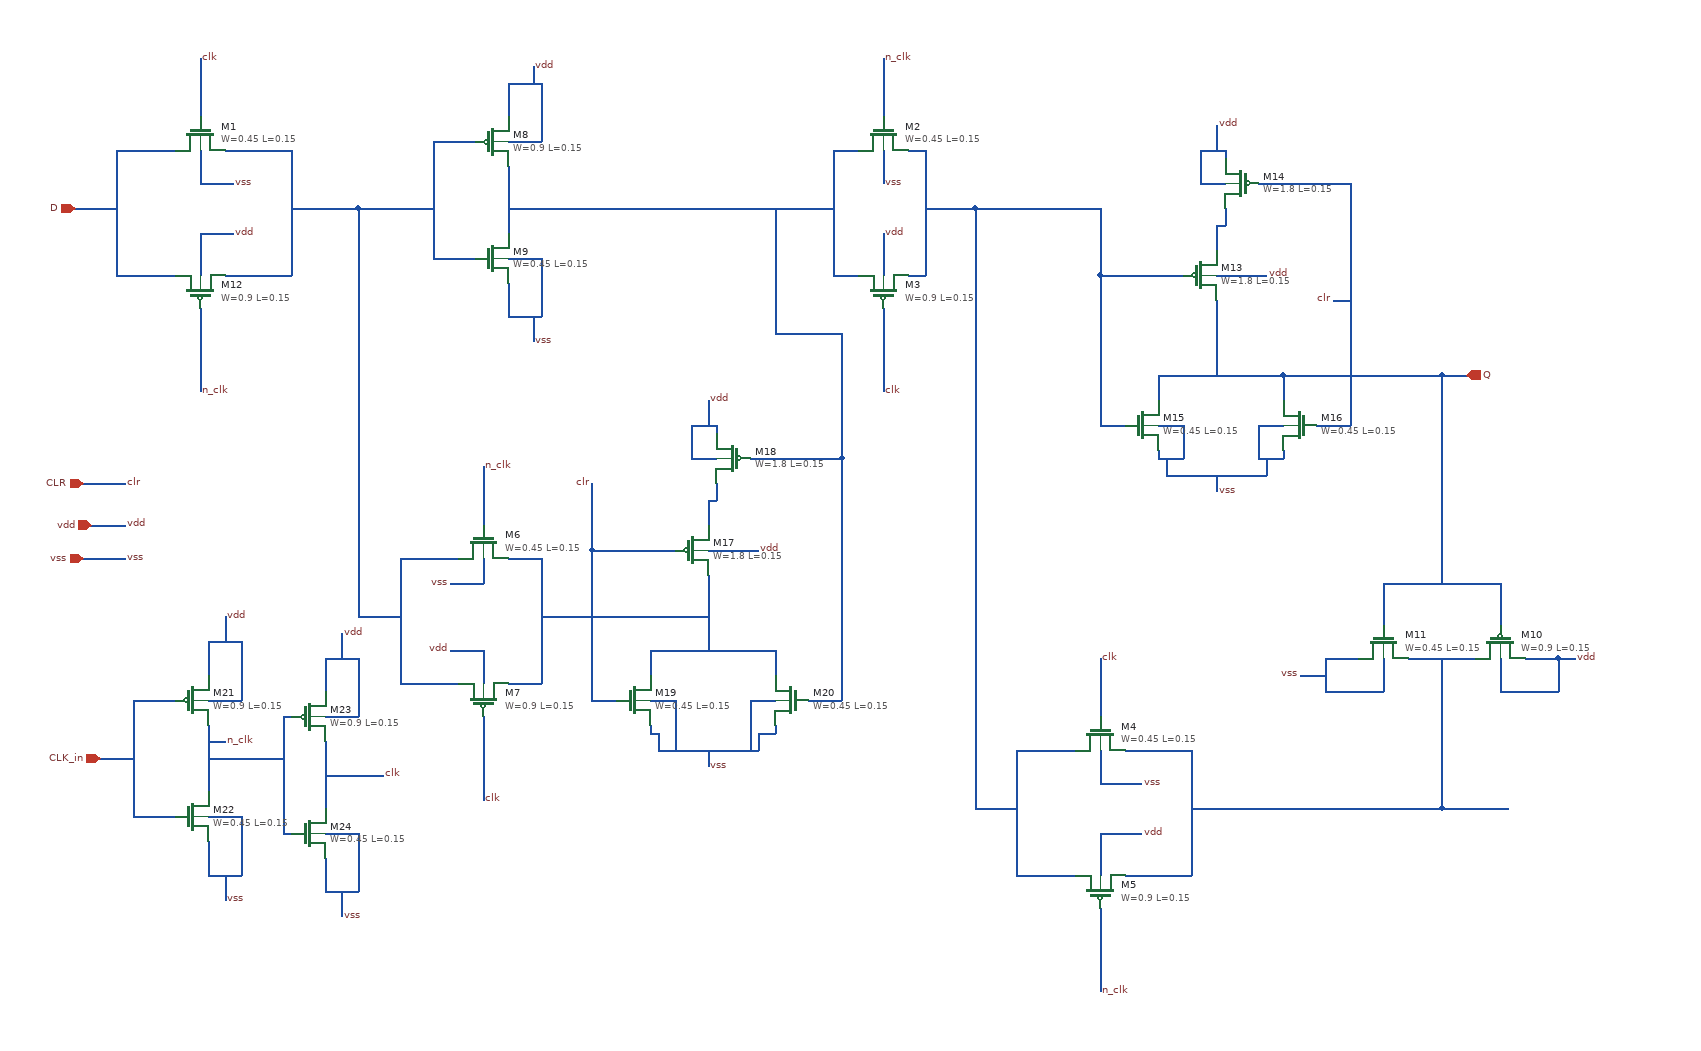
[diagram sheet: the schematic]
v {xschem version=2.9.9 file_version=1.2 }
G {}
K {}
V {}
S {}
E {}
N -920 -130 -910 -130 { lab=D}
N -920 -280 -910 -280 { lab=D}
N -850 -130 -770 -130 { lab=#net1}
N -770 -280 -770 -130 { lab=#net1}
N -850 -280 -770 -280 { lab=#net1}
N -770 -210 -690 -210 { lab=#net1}
N -880 -90 -880 10 { lab=n_clk}
N -880 -390 -880 -320 { lab=clk}
N -980 -280 -920 -280 { lab=D}
N -980 -280 -980 -130 { lab=D}
N -980 -130 -920 -130 { lab=D}
N -1030 -210 -980 -210 { lab=D}
N -60 -170 -60 -130 { lab=vdd}
N -100 -130 -90 -130 { lab=#net2}
N -60 -280 -60 -250 { lab=vss}
N -100 -280 -90 -280 { lab=#net2}
N -10 -280 -10 -130 { lab=#net3}
N -60 -90 -60 10 { lab=clk}
N -60 -390 -60 -320 { lab=n_clk}
N -270 -210 -220 -210 { lab=#net2}
N 200 550 200 590 { lab=vdd}
N 160 590 170 590 { lab=#net3}
N 200 440 200 470 { lab=vss}
N 160 440 170 440 { lab=#net3}
N 230 590 310 590 { lab=#net4}
N 310 440 310 590 { lab=#net4}
N 230 440 310 440 { lab=#net4}
N 310 510 390 510 { lab=#net4}
N 200 630 200 730 { lab=n_clk}
N 200 330 200 400 { lab=clk}
N 100 440 160 440 { lab=#net3}
N 100 440 100 590 { lab=#net3}
N 100 590 160 590 { lab=#net3}
N 50 510 100 510 { lab=#net3}
N -540 320 -540 360 { lab=vdd}
N -580 320 -540 320 { lab=vdd}
N -580 360 -570 360 { lab=#net1}
N -540 210 -540 240 { lab=vss}
N -580 240 -540 240 { lab=vss}
N -580 210 -570 210 { lab=#net1}
N -540 400 -540 500 { lab=clk}
N -540 100 -540 170 { lab=n_clk}
N -640 210 -580 210 { lab=#net1}
N -640 210 -640 360 { lab=#net1}
N -640 360 -580 360 { lab=#net1}
N -690 280 -640 280 { lab=#net1}
N -690 -210 -690 280 { lab=#net1}
N -600 -150 -550 -150 { lab=#net1}
N -600 -290 -600 -150 { lab=#net1}
N -600 -290 -550 -290 { lab=#net1}
N -510 -260 -510 -180 { lab=#net2}
N -510 -150 -470 -150 { lab=vss}
N -470 -150 -470 -80 { lab=vss}
N -510 -80 -470 -80 { lab=vss}
N -510 -120 -510 -80 { lab=vss}
N -510 -290 -470 -290 { lab=vdd}
N -470 -360 -470 -290 { lab=vdd}
N -510 -360 -470 -360 { lab=vdd}
N -510 -360 -510 -320 { lab=vdd}
N -690 -210 -600 -210 { lab=#net1}
N -510 -210 -270 -210 { lab=#net2}
N -470 210 -470 360 { lab=#net5}
N -510 360 -470 360 { lab=#net5}
N -510 210 -470 210 { lab=#net5}
N -470 280 -450 280 { lab=#net5}
N 540 240 540 290 { lab=Q}
N 540 240 680 240 { lab=Q}
N 680 240 680 290 { lab=Q}
N 570 330 650 330 { lab=#net4}
N 540 330 540 370 { lab=vss}
N 470 370 540 370 { lab=vss}
N 470 330 470 370 { lab=vss}
N 470 330 510 330 { lab=vss}
N 680 330 680 370 { lab=vdd}
N 680 370 750 370 { lab=vdd}
N 750 330 750 370 { lab=vdd}
N 710 330 750 330 { lab=vdd}
N 610 330 610 510 { lab=#net4}
N 390 510 610 510 { lab=#net4}
N 610 510 690 510 { lab=#net4}
N 50 -210 50 510 { lab=#net3}
N -10 -210 50 -210 { lab=#net3}
N 340 -190 340 -160 { lab=#net6}
N 320 -240 350 -240 { lab=vdd}
N 320 -280 320 -240 { lab=vdd}
N 320 -280 350 -280 { lab=vdd}
N 350 -280 350 -270 { lab=vdd}
N 270 50 300 50 { lab=vss}
N 300 50 300 90 { lab=vss}
N 270 90 300 90 { lab=vss}
N 270 80 270 90 { lab=vss}
N 420 80 420 90 { lab=vss}
N 390 90 420 90 { lab=vss}
N 390 50 390 90 { lab=vss}
N 390 50 420 50 { lab=vss}
N 280 90 280 110 { lab=vss}
N 280 110 400 110 { lab=vss}
N 400 90 400 110 { lab=vss}
N 340 110 340 130 { lab=vss}
N 270 -10 270 20 { lab=Q}
N 270 -10 420 -10 { lab=Q}
N 420 -10 420 20 { lab=Q}
N 200 50 230 50 { lab=#net3}
N 350 -210 350 -190 { lab=#net6}
N 340 -100 340 -10 { lab=Q}
N 200 -130 300 -130 { lab=#net3}
N 200 -130 200 50 { lab=#net3}
N 50 -210 200 -210 { lab=#net3}
N 200 -210 200 -130 { lab=#net3}
N 390 -240 500 -240 { lab=clr}
N 500 -240 500 50 { lab=clr}
N 460 50 500 50 { lab=clr}
N 480 -100 500 -100 { lab=clr}
N 340 -310 340 -280 { lab=vdd}
N -270 200 -240 200 { lab=vdd}
N -270 140 -270 170 { lab=#net7}
N -290 90 -260 90 { lab=vdd}
N -290 50 -290 90 { lab=vdd}
N -290 50 -260 50 { lab=vdd}
N -260 50 -260 60 { lab=vdd}
N -340 380 -310 380 { lab=vss}
N -340 410 -340 420 { lab=vss}
N -190 410 -190 420 { lab=vss}
N -220 380 -190 380 { lab=vss}
N -330 420 -330 440 { lab=vss}
N -330 440 -210 440 { lab=vss}
N -210 420 -210 440 { lab=vss}
N -270 440 -270 460 { lab=vss}
N -340 320 -340 350 { lab=#net5}
N -340 320 -190 320 { lab=#net5}
N -190 320 -190 350 { lab=#net5}
N -410 380 -380 380 { lab=clr}
N -260 120 -260 140 { lab=#net7}
N -270 230 -270 320 { lab=#net5}
N -410 200 -310 200 { lab=clr}
N -410 200 -410 380 { lab=clr}
N -410 120 -410 200 { lab=clr}
N -220 90 -110 90 { lab=#net2}
N -110 90 -110 380 { lab=#net2}
N -150 380 -110 380 { lab=#net2}
N -270 20 -270 50 { lab=vdd}
N -30 -280 -10 -280 { lab=#net3}
N -30 -130 -10 -130 { lab=#net3}
N -120 -280 -120 -130 { lab=#net2}
N -120 -280 -100 -280 { lab=#net2}
N -120 -130 -100 -130 { lab=#net2}
N -220 -210 -120 -210 { lab=#net2}
N -450 280 -270 280 { lab=#net5}
N -110 -60 -110 90 { lab=#net2}
N -190 -60 -110 -60 { lab=#net2}
N -190 -210 -190 -60 { lab=#net2}
N -960 520 -910 520 { lab=CLK}
N -960 380 -960 520 { lab=CLK}
N -960 380 -910 380 { lab=CLK}
N -870 410 -870 490 { lab=n_clk}
N -870 520 -830 520 { lab=vss}
N -830 520 -830 590 { lab=vss}
N -870 590 -830 590 { lab=vss}
N -870 550 -870 590 { lab=vss}
N -870 380 -830 380 { lab=vdd}
N -830 310 -830 380 { lab=vdd}
N -870 310 -830 310 { lab=vdd}
N -870 310 -870 350 { lab=vdd}
N -870 450 -800 450 { lab=n_clk}
N -1010 450 -960 450 { lab=CLK}
N -850 590 -850 620 { lab=vss}
N -850 280 -850 310 { lab=vdd}
N 420 -10 610 -10 { lab=Q}
N 610 -10 610 240 { lab=Q}
N 610 -10 640 -10 { lab=Q}
N -1020 120 -970 120 { lab=clr}
N -1020 170 -970 170 { lab=vdd}
N -1020 210 -970 210 { lab=vss}
N -480 -380 -480 -360 { lab=vdd}
N 750 330 770 330 { lab=vdd}
N -480 -80 -480 -50 { lab=vss}
N 440 350 470 350 { lab=vss}
N -730 430 -730 510 { lab=clk}
N -730 540 -690 540 { lab=vss}
N -690 540 -690 610 { lab=vss}
N -730 610 -690 610 { lab=vss}
N -730 570 -730 610 { lab=vss}
N -730 400 -690 400 { lab=vdd}
N -690 330 -690 400 { lab=vdd}
N -730 330 -690 330 { lab=vdd}
N -730 330 -730 370 { lab=vdd}
N -730 470 -660 470 { lab=clk}
N -710 610 -710 640 { lab=vss}
N -710 300 -710 330 { lab=vdd}
N -870 430 -850 430 { lab=n_clk}
N -780 400 -770 400 { lab=n_clk}
N -780 400 -780 540 { lab=n_clk}
N -780 540 -770 540 { lab=n_clk}
N -800 450 -780 450 { lab=n_clk}
N -880 -180 -840 -180 { lab=vdd}
N -880 -180 -880 -130 { lab=vdd}
N -880 -240 -840 -240 { lab=vss}
N -880 -280 -880 -240 { lab=vss}
N -60 -180 -60 -170 { lab=vdd}
N -60 -250 -60 -240 { lab=vss}
N 340 -190 350 -190 { lab=#net6}
N 340 -130 400 -130 { lab=vdd}
N 200 540 250 540 { lab=vdd}
N 200 540 200 550 { lab=vdd}
N 200 480 250 480 { lab=vss}
N 200 470 200 480 { lab=vss}
N -340 420 -330 420 { lab=vss}
N -210 420 -190 420 { lab=vss}
N -310 380 -310 440 { lab=vss}
N -220 380 -220 440 { lab=vss}
N -270 140 -260 140 { lab=#net7}
N -240 200 -210 200 { lab=vdd}
C {sky130_fd_pr/nfet_01v8.sym} -880 -300 1 0 {name=M1
L=0.15
W=0.45
nf=1 
mult=1
ad="'int((nf+1)/2) * W/nf * 0.29'" 
pd="'2*int((nf+1)/2) * (W/nf + 0.29)'"
as="'int((nf+2)/2) * W/nf * 0.29'" 
ps="'2*int((nf+2)/2) * (W/nf + 0.29)'"
nrd="'0.29 / W'" nrs="'0.29 / W'"
sa=0 sb=0 sd=0
model=nfet_01v8
spiceprefix=X
}
C {sky130_fd_pr/pfet_01v8.sym} -880 -110 3 0 {name=M12
L=0.15
W=0.9
nf=1
mult=1
ad="'int((nf+1)/2) * W/nf * 0.29'" 
pd="'2*int((nf+1)/2) * (W/nf + 0.29)'"
as="'int((nf+2)/2) * W/nf * 0.29'" 
ps="'2*int((nf+2)/2) * (W/nf + 0.29)'"
nrd="'0.29 / W'" nrs="'0.29 / W'"
sa=0 sb=0 sd=0
model=pfet_01v8
spiceprefix=X
}
C {sky130_fd_pr/nfet_01v8.sym} -60 -300 1 0 {name=M2
L=0.15
W=0.45
nf=1 
mult=1
ad="'int((nf+1)/2) * W/nf * 0.29'" 
pd="'2*int((nf+1)/2) * (W/nf + 0.29)'"
as="'int((nf+2)/2) * W/nf * 0.29'" 
ps="'2*int((nf+2)/2) * (W/nf + 0.29)'"
nrd="'0.29 / W'" nrs="'0.29 / W'"
sa=0 sb=0 sd=0
model=nfet_01v8
spiceprefix=X
}
C {sky130_fd_pr/pfet_01v8.sym} -60 -110 3 0 {name=M3
L=0.15
W=0.9
nf=1
mult=1
ad="'int((nf+1)/2) * W/nf * 0.29'" 
pd="'2*int((nf+1)/2) * (W/nf + 0.29)'"
as="'int((nf+2)/2) * W/nf * 0.29'" 
ps="'2*int((nf+2)/2) * (W/nf + 0.29)'"
nrd="'0.29 / W'" nrs="'0.29 / W'"
sa=0 sb=0 sd=0
model=pfet_01v8
spiceprefix=X
}
C {sky130_fd_pr/nfet_01v8.sym} 200 420 1 0 {name=M4
L=0.15
W=0.45
nf=1 
mult=1
ad="'int((nf+1)/2) * W/nf * 0.29'" 
pd="'2*int((nf+1)/2) * (W/nf + 0.29)'"
as="'int((nf+2)/2) * W/nf * 0.29'" 
ps="'2*int((nf+2)/2) * (W/nf + 0.29)'"
nrd="'0.29 / W'" nrs="'0.29 / W'"
sa=0 sb=0 sd=0
model=nfet_01v8
spiceprefix=X
}
C {sky130_fd_pr/pfet_01v8.sym} 200 610 3 0 {name=M5
L=0.15
W=0.9
nf=1
mult=1
ad="'int((nf+1)/2) * W/nf * 0.29'" 
pd="'2*int((nf+1)/2) * (W/nf + 0.29)'"
as="'int((nf+2)/2) * W/nf * 0.29'" 
ps="'2*int((nf+2)/2) * (W/nf + 0.29)'"
nrd="'0.29 / W'" nrs="'0.29 / W'"
sa=0 sb=0 sd=0
model=pfet_01v8
spiceprefix=X
}
C {sky130_fd_pr/nfet_01v8.sym} -540 190 1 0 {name=M6
L=0.15
W=0.45
nf=1 
mult=1
ad="'int((nf+1)/2) * W/nf * 0.29'" 
pd="'2*int((nf+1)/2) * (W/nf + 0.29)'"
as="'int((nf+2)/2) * W/nf * 0.29'" 
ps="'2*int((nf+2)/2) * (W/nf + 0.29)'"
nrd="'0.29 / W'" nrs="'0.29 / W'"
sa=0 sb=0 sd=0
model=nfet_01v8
spiceprefix=X
}
C {sky130_fd_pr/pfet_01v8.sym} -540 380 3 0 {name=M7
L=0.15
W=0.9
nf=1
mult=1
ad="'int((nf+1)/2) * W/nf * 0.29'" 
pd="'2*int((nf+1)/2) * (W/nf + 0.29)'"
as="'int((nf+2)/2) * W/nf * 0.29'" 
ps="'2*int((nf+2)/2) * (W/nf + 0.29)'"
nrd="'0.29 / W'" nrs="'0.29 / W'"
sa=0 sb=0 sd=0
model=pfet_01v8
spiceprefix=X
}
C {sky130_fd_pr/pfet_01v8.sym} -530 -290 0 0 {name=M8
L=0.15
W=0.9
nf=1
mult=1
ad="'int((nf+1)/2) * W/nf * 0.29'" 
pd="'2*int((nf+1)/2) * (W/nf + 0.29)'"
as="'int((nf+2)/2) * W/nf * 0.29'" 
ps="'2*int((nf+2)/2) * (W/nf + 0.29)'"
nrd="'0.29 / W'" nrs="'0.29 / W'"
sa=0 sb=0 sd=0
model=pfet_01v8
spiceprefix=X
}
C {sky130_fd_pr/nfet_01v8.sym} -530 -150 0 0 {name=M9
L=0.15
W=0.45
nf=1 
mult=1
ad="'int((nf+1)/2) * W/nf * 0.29'" 
pd="'2*int((nf+1)/2) * (W/nf + 0.29)'"
as="'int((nf+2)/2) * W/nf * 0.29'" 
ps="'2*int((nf+2)/2) * (W/nf + 0.29)'"
nrd="'0.29 / W'" nrs="'0.29 / W'"
sa=0 sb=0 sd=0
model=nfet_01v8
spiceprefix=X
}
C {sky130_fd_pr/pfet_01v8.sym} 680 310 1 0 {name=M10
L=0.15
W=0.9
nf=1
mult=1
ad="'int((nf+1)/2) * W/nf * 0.29'" 
pd="'2*int((nf+1)/2) * (W/nf + 0.29)'"
as="'int((nf+2)/2) * W/nf * 0.29'" 
ps="'2*int((nf+2)/2) * (W/nf + 0.29)'"
nrd="'0.29 / W'" nrs="'0.29 / W'"
sa=0 sb=0 sd=0
model=pfet_01v8
spiceprefix=X
}
C {sky130_fd_pr/nfet_01v8.sym} 540 310 1 0 {name=M11
L=0.15
W=0.45
nf=1 
mult=1
ad="'int((nf+1)/2) * W/nf * 0.29'" 
pd="'2*int((nf+1)/2) * (W/nf + 0.29)'"
as="'int((nf+2)/2) * W/nf * 0.29'" 
ps="'2*int((nf+2)/2) * (W/nf + 0.29)'"
nrd="'0.29 / W'" nrs="'0.29 / W'"
sa=0 sb=0 sd=0
model=nfet_01v8
spiceprefix=X
}
C {sky130_fd_pr/pfet_01v8.sym} 320 -130 0 0 {name=M13
L=0.15
W=1.8
nf=1
mult=1
ad="'int((nf+1)/2) * W/nf * 0.29'" 
pd="'2*int((nf+1)/2) * (W/nf + 0.29)'"
as="'int((nf+2)/2) * W/nf * 0.29'" 
ps="'2*int((nf+2)/2) * (W/nf + 0.29)'"
nrd="'0.29 / W'" nrs="'0.29 / W'"
sa=0 sb=0 sd=0
model=pfet_01v8
spiceprefix=X
}
C {sky130_fd_pr/pfet_01v8.sym} 370 -240 0 1 {name=M14
L=0.15
W=1.8
nf=1
mult=1
ad="'int((nf+1)/2) * W/nf * 0.29'" 
pd="'2*int((nf+1)/2) * (W/nf + 0.29)'"
as="'int((nf+2)/2) * W/nf * 0.29'" 
ps="'2*int((nf+2)/2) * (W/nf + 0.29)'"
nrd="'0.29 / W'" nrs="'0.29 / W'"
sa=0 sb=0 sd=0
model=pfet_01v8
spiceprefix=X
}
C {sky130_fd_pr/nfet_01v8.sym} 250 50 0 0 {name=M15
L=0.15
W=0.45
nf=1 
mult=1
ad="'int((nf+1)/2) * W/nf * 0.29'" 
pd="'2*int((nf+1)/2) * (W/nf + 0.29)'"
as="'int((nf+2)/2) * W/nf * 0.29'" 
ps="'2*int((nf+2)/2) * (W/nf + 0.29)'"
nrd="'0.29 / W'" nrs="'0.29 / W'"
sa=0 sb=0 sd=0
model=nfet_01v8
spiceprefix=X
}
C {sky130_fd_pr/nfet_01v8.sym} 440 50 0 1 {name=M16
L=0.15
W=0.45
nf=1 
mult=1
ad="'int((nf+1)/2) * W/nf * 0.29'" 
pd="'2*int((nf+1)/2) * (W/nf + 0.29)'"
as="'int((nf+2)/2) * W/nf * 0.29'" 
ps="'2*int((nf+2)/2) * (W/nf + 0.29)'"
nrd="'0.29 / W'" nrs="'0.29 / W'"
sa=0 sb=0 sd=0
model=nfet_01v8
spiceprefix=X
}
C {sky130_fd_pr/pfet_01v8.sym} -290 200 0 0 {name=M17
L=0.15
W=1.8
nf=1
mult=1
ad="'int((nf+1)/2) * W/nf * 0.29'" 
pd="'2*int((nf+1)/2) * (W/nf + 0.29)'"
as="'int((nf+2)/2) * W/nf * 0.29'" 
ps="'2*int((nf+2)/2) * (W/nf + 0.29)'"
nrd="'0.29 / W'" nrs="'0.29 / W'"
sa=0 sb=0 sd=0
model=pfet_01v8
spiceprefix=X
}
C {sky130_fd_pr/pfet_01v8.sym} -240 90 0 1 {name=M18
L=0.15
W=1.8
nf=1
mult=1
ad="'int((nf+1)/2) * W/nf * 0.29'" 
pd="'2*int((nf+1)/2) * (W/nf + 0.29)'"
as="'int((nf+2)/2) * W/nf * 0.29'" 
ps="'2*int((nf+2)/2) * (W/nf + 0.29)'"
nrd="'0.29 / W'" nrs="'0.29 / W'"
sa=0 sb=0 sd=0
model=pfet_01v8
spiceprefix=X
}
C {sky130_fd_pr/nfet_01v8.sym} -360 380 0 0 {name=M19
L=0.15
W=0.45
nf=1 
mult=1
ad="'int((nf+1)/2) * W/nf * 0.29'" 
pd="'2*int((nf+1)/2) * (W/nf + 0.29)'"
as="'int((nf+2)/2) * W/nf * 0.29'" 
ps="'2*int((nf+2)/2) * (W/nf + 0.29)'"
nrd="'0.29 / W'" nrs="'0.29 / W'"
sa=0 sb=0 sd=0
model=nfet_01v8
spiceprefix=X
}
C {sky130_fd_pr/nfet_01v8.sym} -170 380 0 1 {name=M20
L=0.15
W=0.45
nf=1 
mult=1
ad="'int((nf+1)/2) * W/nf * 0.29'" 
pd="'2*int((nf+1)/2) * (W/nf + 0.29)'"
as="'int((nf+2)/2) * W/nf * 0.29'" 
ps="'2*int((nf+2)/2) * (W/nf + 0.29)'"
nrd="'0.29 / W'" nrs="'0.29 / W'"
sa=0 sb=0 sd=0
model=nfet_01v8
spiceprefix=X
}
C {sky130_fd_pr/pfet_01v8.sym} -890 380 0 0 {name=M21
L=0.15
W=0.9
nf=1
mult=1
ad="'int((nf+1)/2) * W/nf * 0.29'" 
pd="'2*int((nf+1)/2) * (W/nf + 0.29)'"
as="'int((nf+2)/2) * W/nf * 0.29'" 
ps="'2*int((nf+2)/2) * (W/nf + 0.29)'"
nrd="'0.29 / W'" nrs="'0.29 / W'"
sa=0 sb=0 sd=0
model=pfet_01v8
spiceprefix=X
}
C {sky130_fd_pr/nfet_01v8.sym} -890 520 0 0 {name=M22
L=0.15
W=0.45
nf=1 
mult=1
ad="'int((nf+1)/2) * W/nf * 0.29'" 
pd="'2*int((nf+1)/2) * (W/nf + 0.29)'"
as="'int((nf+2)/2) * W/nf * 0.29'" 
ps="'2*int((nf+2)/2) * (W/nf + 0.29)'"
nrd="'0.29 / W'" nrs="'0.29 / W'"
sa=0 sb=0 sd=0
model=nfet_01v8
spiceprefix=X
}
C {ipin.sym} -1030 -210 0 0 {name=p1 lab=D}
C {ipin.sym} -1000 450 0 0 {name=p2 lab=CLK_in}
C {ipin.sym} -1020 120 0 0 {name=p3 lab=CLR}
C {opin.sym} 640 -10 0 0 {name=p4 lab=Q}
C {lab_pin.sym} -970 120 2 0 {name=l2 sig_type=std_logic lab=clr}
C {ipin.sym} -1010 170 0 0 {name=p6 lab=vdd}
C {ipin.sym} -1020 210 0 0 {name=p7 lab=vss}
C {lab_pin.sym} -970 170 2 0 {name=l3 sig_type=std_logic lab=vdd}
C {lab_pin.sym} -970 210 2 0 {name=l4 sig_type=std_logic lab=vss}
C {lab_pin.sym} -880 -390 2 0 {name=l5 sig_type=std_logic lab=clk}
C {lab_pin.sym} -60 10 2 0 {name=l6 sig_type=std_logic lab=clk}
C {lab_pin.sym} 200 330 2 0 {name=l7 sig_type=std_logic lab=clk}
C {lab_pin.sym} -540 500 2 0 {name=l8 sig_type=std_logic lab=clk}
C {lab_pin.sym} -850 430 2 0 {name=l10 sig_type=std_logic lab=n_clk}
C {lab_pin.sym} -540 100 2 0 {name=l11 sig_type=std_logic lab=n_clk}
C {lab_pin.sym} -880 10 2 0 {name=l12 sig_type=std_logic lab=n_clk}
C {lab_pin.sym} -60 -390 2 0 {name=l13 sig_type=std_logic lab=n_clk}
C {lab_pin.sym} 200 730 2 0 {name=l14 sig_type=std_logic lab=n_clk}
C {lab_pin.sym} 480 -100 0 0 {name=l15 sig_type=std_logic lab=clr}
C {lab_pin.sym} -410 120 0 0 {name=l16 sig_type=std_logic lab=clr}
C {lab_pin.sym} -480 -380 2 0 {name=l17 sig_type=std_logic lab=vdd}
C {lab_pin.sym} 340 -310 2 0 {name=l18 sig_type=std_logic lab=vdd}
C {lab_pin.sym} 770 330 2 0 {name=l19 sig_type=std_logic lab=vdd}
C {lab_pin.sym} -270 20 2 0 {name=l20 sig_type=std_logic lab=vdd}
C {lab_pin.sym} -850 280 2 0 {name=l21 sig_type=std_logic lab=vdd}
C {lab_pin.sym} -850 620 2 0 {name=l22 sig_type=std_logic lab=vss}
C {lab_pin.sym} -480 -50 2 0 {name=l23 sig_type=std_logic lab=vss}
C {lab_pin.sym} -270 460 2 0 {name=l24 sig_type=std_logic lab=vss}
C {lab_pin.sym} 340 130 2 0 {name=l25 sig_type=std_logic lab=vss}
C {lab_pin.sym} 440 350 0 0 {name=l26 sig_type=std_logic lab=vss}
C {sky130_fd_pr/pfet_01v8.sym} -750 400 0 0 {name=M23
L=0.15
W=0.9
nf=1
mult=1
ad="'int((nf+1)/2) * W/nf * 0.29'" 
pd="'2*int((nf+1)/2) * (W/nf + 0.29)'"
as="'int((nf+2)/2) * W/nf * 0.29'" 
ps="'2*int((nf+2)/2) * (W/nf + 0.29)'"
nrd="'0.29 / W'" nrs="'0.29 / W'"
sa=0 sb=0 sd=0
model=pfet_01v8
spiceprefix=X
}
C {sky130_fd_pr/nfet_01v8.sym} -750 540 0 0 {name=M24
L=0.15
W=0.45
nf=1 
mult=1
ad="'int((nf+1)/2) * W/nf * 0.29'" 
pd="'2*int((nf+1)/2) * (W/nf + 0.29)'"
as="'int((nf+2)/2) * W/nf * 0.29'" 
ps="'2*int((nf+2)/2) * (W/nf + 0.29)'"
nrd="'0.29 / W'" nrs="'0.29 / W'"
sa=0 sb=0 sd=0
model=nfet_01v8
spiceprefix=X
}
C {lab_pin.sym} -660 470 2 0 {name=l27 sig_type=std_logic lab=clk}
C {lab_pin.sym} -710 300 2 0 {name=l28 sig_type=std_logic lab=vdd}
C {lab_pin.sym} -710 640 2 0 {name=l29 sig_type=std_logic lab=vss}
C {lab_pin.sym} -840 -180 2 0 {name=l30 sig_type=std_logic lab=vdd}
C {lab_pin.sym} -840 -240 2 0 {name=l31 sig_type=std_logic lab=vss}
C {lab_pin.sym} -60 -180 2 0 {name=l32 sig_type=std_logic lab=vdd}
C {lab_pin.sym} -60 -240 2 0 {name=l33 sig_type=std_logic lab=vss}
C {lab_pin.sym} 400 -130 2 0 {name=l34 sig_type=std_logic lab=vdd}
C {lab_pin.sym} 250 480 2 0 {name=l35 sig_type=std_logic lab=vss}
C {lab_pin.sym} 250 540 2 0 {name=l36 sig_type=std_logic lab=vdd}
C {lab_pin.sym} -210 200 2 0 {name=l37 sig_type=std_logic lab=vdd}
C {lab_pin.sym} -580 320 0 0 {name=l38 sig_type=std_logic lab=vdd}
C {lab_pin.sym} -580 240 0 0 {name=l39 sig_type=std_logic lab=vss}
